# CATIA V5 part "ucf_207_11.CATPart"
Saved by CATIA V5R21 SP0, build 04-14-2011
Part number: ucf_207_11
Bounding box of the stored display mesh (mm): x -25.963 to -15.02, y -5.556 to 5.556, z 11.723 to 22.666
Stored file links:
  C:\TPO v2\SharedFS\Outgoing\ucf_207_11.CATPart

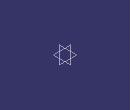
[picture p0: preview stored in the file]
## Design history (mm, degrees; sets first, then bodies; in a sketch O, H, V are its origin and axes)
AxisSystem1: origin (0, 0, 0), X (1, 0, 0), Y (0, 1, 0), Z (0, 0, 1)
Body1 "ucf_207_11" (main body)
  Solid1: solid without history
